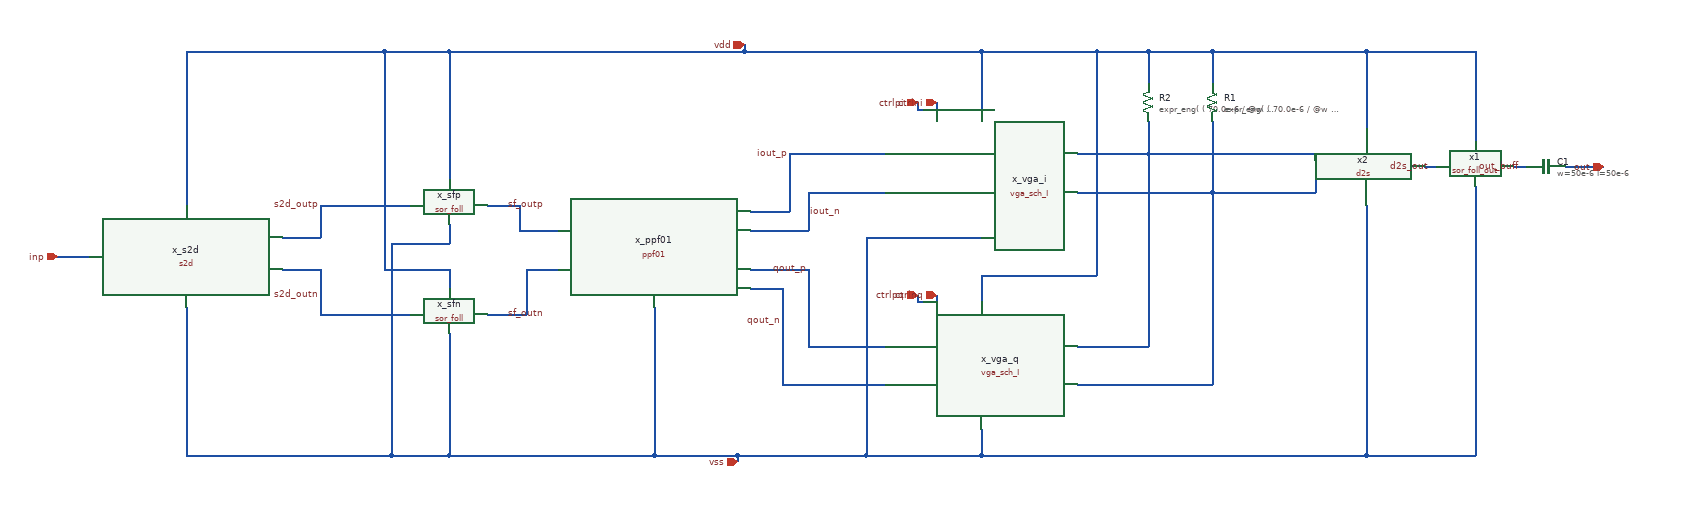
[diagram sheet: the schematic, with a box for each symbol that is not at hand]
v {xschem version=3.4.8RC file_version=1.3}
G {}
K {}
V {}
S {}
F {}
E {}
N 4900 -1340 4960 -1340 {lab=s2d_outp}
N 4960 -1390 4960 -1340 {lab=s2d_outp}
N 4960 -1390 5100 -1390 {lab=s2d_outp}
N 4960 -1220 5100 -1220 {lab=s2d_outn}
N 4900 -1290 4960 -1290 {lab=s2d_outn}
N 4960 -1290 4960 -1220 {lab=s2d_outn}
N 5220 -1390 5270 -1390 {lab=sf_outp}
N 5270 -1390 5270 -1350 {lab=sf_outp}
N 5270 -1350 5330 -1350 {lab=sf_outp}
N 5220 -1220 5280 -1220 {lab=sf_outn}
N 5280 -1290 5280 -1220 {lab=sf_outn}
N 5280 -1290 5330 -1290 {lab=sf_outn}
N 5630 -1380 5690 -1380 {lab=iout_p}
N 5690 -1470 5690 -1380 {lab=iout_p}
N 5690 -1470 5840 -1470 {lab=iout_p}
N 5630 -1350 5720 -1350 {lab=iout_n}
N 5720 -1410 5720 -1350 {lab=iout_n}
N 5720 -1410 5840 -1410 {lab=iout_n}
N 5630 -1260 5680 -1260 {lab=qout_n}
N 5680 -1260 5680 -1110 {lab=qout_n}
N 5680 -1110 5840 -1110 {lab=qout_n}
N 5630 -1290 5720 -1290 {lab=qout_p}
N 5720 -1290 5720 -1170 {lab=qout_p}
N 5720 -1170 5840 -1170 {lab=qout_p}
N 6250 -1470 6250 -1170 {lab=#net1}
N 6350 -1410 6350 -1110 {lab=#net2}
N 4750 -1230 4750 -1000 {lab=vss}
N 5990 -1040 5990 -1000 {lab=vss}
N 5160 -1190 5160 -1000 {lab=vss}
N 5070 -1000 5160 -1000 {lab=vss}
N 5160 -1360 5160 -1330 {lab=vss}
N 5070 -1330 5160 -1330 {lab=vss}
N 5070 -1330 5070 -1000 {lab=vss}
N 4750 -1000 5070 -1000 {lab=vss}
N 5480 -1230 5480 -1000 {lab=vss}
N 5160 -1000 5480 -1000 {lab=vss}
N 6250 -1630 6350 -1630 {lab=vdd}
N 5160 -1290 5160 -1260 {lab=vdd}
N 5060 -1290 5160 -1290 {lab=vdd}
N 5160 -1630 5620 -1630 {lab=vdd}
N 4550 -1310 4600 -1310 {lab=inp}
N 6250 -1520 6250 -1470 {lab=#net1}
N 6350 -1520 6350 -1410 {lab=#net2}
N 6140 -1470 6250 -1470 {lab=#net1}
N 6140 -1170 6250 -1170 {lab=#net1}
N 6140 -1410 6350 -1410 {lab=#net2}
N 6140 -1110 6350 -1110 {lab=#net2}
N 5620 -1640 5620 -1630 {lab=vdd}
N 5610 -1000 5610 -990 {lab=vss}
N 5480 -1000 5610 -1000 {lab=vss}
N 5890 -1550 5890 -1540 {lab=ctrlpi}
N 5890 -1540 5900 -1540 {lab=ctrlpi}
N 5920 -1550 5920 -1540 {lab=ctrlni}
N 4750 -1630 4750 -1390 {lab=vdd}
N 5060 -1630 5060 -1290 {lab=vdd}
N 4750 -1630 5060 -1630 {lab=vdd}
N 5160 -1630 5160 -1430 {lab=vdd}
N 5060 -1630 5160 -1630 {lab=vdd}
N 5990 -1630 5990 -1540 {lab=vdd}
N 5620 -1630 5990 -1630 {lab=vdd}
N 6250 -1630 6250 -1580 {lab=vdd}
N 6170 -1630 6250 -1630 {lab=vdd}
N 6350 -1630 6350 -1580 {lab=vdd}
N 5890 -1250 5890 -1240 {lab=ctrlpq}
N 5890 -1240 5900 -1240 {lab=ctrlpq}
N 5920 -1250 5920 -1240 {lab=ctrlnq}
N 5810 -1340 5990 -1340 {lab=vss}
N 5810 -1340 5810 -1000 {lab=vss}
N 5610 -1000 5810 -1000 {lab=vss}
N 5990 -1280 5990 -1240 {lab=vdd}
N 5990 -1280 6170 -1280 {lab=vdd}
N 6170 -1630 6170 -1280 {lab=vdd}
N 5990 -1630 6170 -1630 {lab=vdd}
N 6510 -1440 6510 -1410 {lab=#net2}
N 6510 -1470 6510 -1460 {lab=#net1}
N 6680 -1450 6700 -1450 {lab=d2s_out}
N 6590 -1630 6760 -1630 {lab=vdd}
N 6590 -1000 6760 -1000 {lab=vss}
N 6760 -1420 6760 -1000 {lab=vss}
N 6590 -1390 6590 -1000 {lab=vss}
N 6250 -1470 6510 -1470 {lab=#net1}
N 6350 -1410 6510 -1410 {lab=#net2}
N 6590 -1630 6590 -1510 {lab=vdd}
N 6350 -1630 6590 -1630 {lab=vdd}
N 5990 -1000 6590 -1000 {lab=vss}
N 5810 -1000 5990 -1000 {lab=vss}
N 6760 -1630 6760 -1490 {lab=vdd}
N 6820 -1450 6840 -1450 {lab=out_buff}
N 6900 -1450 6960 -1450 {lab=out}
C {05_vga/vga_sch_I.sym} 5990 -1440 0 0 {name=x_vga_i}
C {02_s2d/s2d.sym} 4750 -1310 0 0 {name=x_s2d
type=blank_circuit}
C {03_sor_foll/sor_foll.sym} 5170 -1390 0 0 {name=x_sfp}
C {03_sor_foll/sor_foll.sym} 5170 -1220 0 0 {name=x_sfn}
C {04_iq_ppf/ppf01.sym} 5480 -1320 0 0 {name=x_ppf01}
C {05_vga/vga_sch_I.sym} 5990 -1140 0 0 {name=x_vga_q}
C {iopin.sym} 4550 -1310 2 0 {name=p1 lab=inp}
C {iopin.sym} 6960 -1450 0 0 {name=p2 lab=out}
C {iopin.sym} 5620 -1640 3 0 {name=p4 lab=vdd}
C {iopin.sym} 5610 -990 1 0 {name=p5 lab=vss}
C {iopin.sym} 5890 -1550 3 0 {name=p6 lab=ctrlpi}
C {iopin.sym} 5920 -1550 3 0 {name=p7 lab=ctrlni}
C {iopin.sym} 5890 -1250 3 0 {name=p8 lab=ctrlpq}
C {iopin.sym} 5920 -1250 3 0 {name=p9 lab=ctrlnq}
C {sg13g2_pr/rppd.sym} 6250 -1550 0 1 {name=R2
w=2e-6
l=2.05e-6
model=rppd
body=vss
spiceprefix=X
b=0
m=1
value="expr_eng(  ( 70.0e-6 / @w + 260.0 * ( (@b + 1)* @l + ( 1.081*( @w + 6.0e-9 ) + 0.18e-6 )*@b ) / ( @w + 6.0e-9 ) ) / @m  )"
}
C {sg13g2_pr/rppd.sym} 6350 -1550 0 0 {name=R1
w=2e-6
l=2.05e-6
model=rppd
body=vss
spiceprefix=X
b=0
m=1
value="expr_eng(  ( 70.0e-6 / @w + 260.0 * ( (@b + 1)* @l + ( 1.081*( @w + 6.0e-9 ) + 0.18e-6 )*@b ) / ( @w + 6.0e-9 ) ) / @m  )"
}
C {lab_wire.sym} 4960 -1390 0 0 {name=p10 sig_type=std_logic lab=s2d_outp
}
C {lab_wire.sym} 4960 -1250 0 0 {name=p11 sig_type=std_logic lab=s2d_outn
}
C {lab_wire.sym} 5250 -1390 0 1 {name=p12 sig_type=std_logic lab=sf_outp
}
C {lab_wire.sym} 5250 -1220 0 1 {name=p13 sig_type=std_logic lab=sf_outn
}
C {lab_wire.sym} 5690 -1470 0 0 {name=p14 sig_type=std_logic lab=iout_p
}
C {lab_wire.sym} 5720 -1380 0 1 {name=p15 sig_type=std_logic lab=iout_n
}
C {lab_wire.sym} 5720 -1290 0 0 {name=p16 sig_type=std_logic lab=qout_p
}
C {lab_wire.sym} 5680 -1210 0 0 {name=p17 sig_type=std_logic lab=qout_n
}
C {05a_d2s/d2s.sym} 6590 -1450 0 0 {name=x2}
C {03_sor_foll/sor_foll_out.sym} 6770 -1450 0 0 {name=x1}
C {devices/lab_pin.sym} 6690 -1450 1 0 {name=p20 sig_type=std_logic lab=d2s_out
}
C {sg13g2_pr/cap_cmim.sym} 6870 -1450 3 0 {name=C1
model=cap_cmim
w=50e-6
l=50e-6
m=2
spiceprefix=X}
C {devices/lab_pin.sym} 6830 -1450 1 0 {name=p3 sig_type=std_logic lab=out_buff
}
